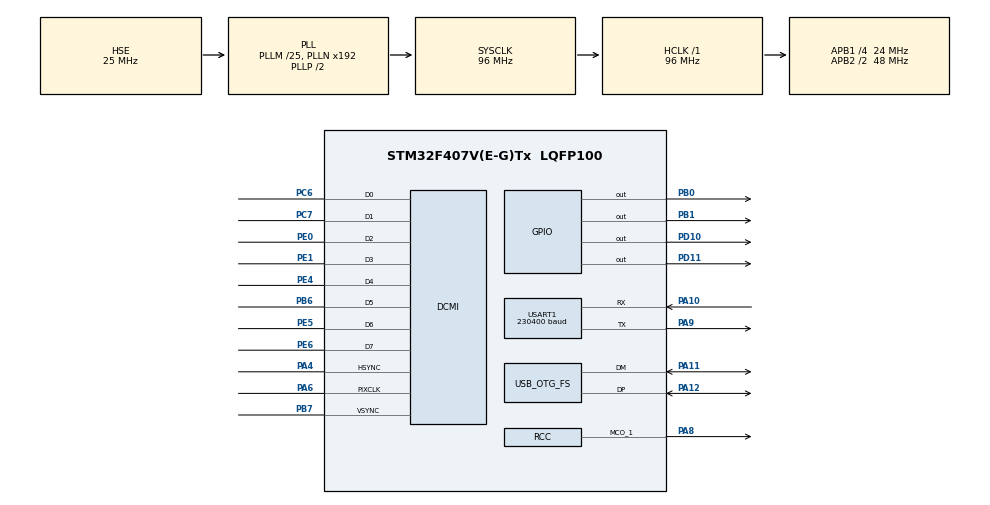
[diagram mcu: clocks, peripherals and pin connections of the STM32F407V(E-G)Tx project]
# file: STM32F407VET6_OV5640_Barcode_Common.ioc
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Mcu.Family=STM32F4
PA6.Mode=Slave_8_bits_External_Synchro
USB_DEVICE.CLASS_NAME_FS=CDC
PH0-OSC_IN.Signal=RCC_OSC_IN
RCC.CortexFreq_Value=96000000
DCMI.HSPolarity=DCMI_HSPOLARITY_LOW
Dma.USART1_TX.1.MemInc=DMA_MINC_ENABLE
PA10.GPIO_PuPd=GPIO_NOPULL
USART1.BaudRate=230400
PA11.Mode=Device_Only
USB_DEVICE.VirtualMode-CDC_FS=Cdc
Dma.DCMI.0.MemBurst=DMA_MBURST_SINGLE
RCC.SYSCLKSource=RCC_SYSCLKSOURCE_PLLCLK
ProjectManager.StackSize=0x2000
Dma.DCMI.0.FIFOMode=DMA_FIFOMODE_ENABLE
Dma.DCMI.0.MemDataAlignment=DMA_MDATAALIGN_WORD
Dma.USART1_TX.1.MemBurst=DMA_MBURST_SINGLE
Dma.DCMI.0.FIFOThreshold=DMA_FIFO_THRESHOLD_FULL
Dma.DCMI.0.MemInc=DMA_MINC_DISABLE
PA12.Signal=USB_OTG_FS_DP
PA4.Mode=Slave_8_bits_External_Synchro
Dma.DCMI.0.PeriphDataAlignment=DMA_PDATAALIGN_WORD
PB0.PinState=GPIO_PIN_SET
PB1.GPIO_PuPd=GPIO_PULLUP
RCC.HCLKFreq_Value=96000000
RCC.APB2TimFreq_Value=96000000
PB6.Signal=DCMI_D5
DCMI.VSPolarity=DCMI_VSPOLARITY_HIGH
PC7.Signal=DCMI_D1
PB6.Mode=Slave_8_bits_External_Synchro
PE5.Signal=DCMI_D6
PE1.Signal=DCMI_D3
RCC.AHBFreq_Value=96000000
PH0-OSC_IN.Mode=HSE-External-Oscillator
RCC.HSE_VALUE=25000000
PA4.GPIO_PuPd=GPIO_NOPULL
RCC.RCC_MCO1Source=RCC_MCO1SOURCE_PLLCLK
DCMI.PCKPolarity=DCMI_PCKPOLARITY_RISING
PA6.GPIO_PuPd=GPIO_NOPULL
PB1.GPIO_Speed=GPIO_SPEED_FREQ_VERY_HIGH
Dma.USART1_TX.1.FIFOThreshold=DMA_FIFO_THRESHOLD_FULL
RCC.RCC_MCODiv1=RCC_MCODIV_4
PB7.Signal=DCMI_VSYNC
PA8.Signal=RCC_MCO_1
Dma.DCMI.0.PeriphBurst=DMA_PBURST_SINGLE
PE4.Mode=Slave_8_bits_External_Synchro
PE4.Signal=DCMI_D4
Dma.USART1_TX.1.PeriphDataAlignment=DMA_PDATAALIGN_BYTE
PB1.PinState=GPIO_PIN_SET
PH1-OSC_OUT.Mode=HSE-External-Oscillator
Mcu.Package=LQFP100
PB1.Signal=GPIO_Output
PA6.Signal=DCMI_PIXCLK
NVIC.DMA2_Stream7_IRQn=true\:0\:0\:false\:false\:true\:false\:true
Dma.DCMI.0.Direction=DMA_PERIPH_TO_MEMORY
NVIC.OTG_FS_IRQn=true\:0\:0\:false\:false\:true\:true\:true
PA10.Signal=USART1_RX
USB_OTG_FS.VirtualMode=Device_Only
PA10.GPIO_Speed=GPIO_SPEED_FREQ_HIGH
RCC.APB2CLKDivider=RCC_HCLK_DIV2
Dma.Request1=USART1_TX
RCC.APB1TimFreq_Value=48000000
PB0.GPIO_ModeDefaultOutputPP=GPIO_MODE_OUTPUT_PP
Dma.USART1_TX.1.Priority=DMA_PRIORITY_MEDIUM
PA6.GPIO_Speed=GPIO_SPEED_FREQ_VERY_HIGH
NVIC.USART1_IRQn=true\:1\:0\:true\:true\:true\:1\:true\:true
Dma.Request0=DCMI
Dma.USART1_TX.1.Direction=DMA_MEMORY_TO_PERIPH
PB7.GPIO_PuPd=GPIO_NOPULL
Dma.USART1_TX.1.Instance=DMA2_Stream7
PA10.Mode=Asynchronous
USB_DEVICE.VirtualModeFS=Cdc_FS
PE1.Mode=Slave_8_bits_External_Synchro
PC6.Signal=DCMI_D0
NVIC.DMA2_Stream1_IRQn=true\:0\:0\:false\:false\:true\:false\:true
RCC.APB1CLKDivider=RCC_HCLK_DIV4
PB0.GPIO_Speed=GPIO_SPEED_FREQ_VERY_HIGH
PD10.Signal=GPIO_Output
Dma.USART1_TX.1.PeriphBurst=DMA_PBURST_SINGLE
PA9.Mode=Asynchronous
ProjectManager.TargetToolchain=STM32CubeIDE
PC6.Mode=Slave_8_bits_External_Synchro
VP_USB_DEVICE_VS_USB_DEVICE_CDC_FS.Mode=CDC_FS
PA9.Signal=USART1_TX
Dma.DCMI.0.Instance=DMA2_Stream1
Dma.DCMI.0.Mode=DMA_NORMAL
Dma.USART1_TX.1.FIFOMode=DMA_FIFOMODE_ENABLE
RCC.LSE_VALUE=32768
DCMI.JPEGMode=DCMI_JPEG_DISABLE
Dma.USART1_TX.1.MemDataAlignment=DMA_MDATAALIGN_BYTE
board=custom
RCC.VCOOutputFreq_Value=192000000
RCC.APB2Freq_Value=48000000
PE6.Mode=Slave_8_bits_External_Synchro
PE5.Mode=Slave_8_bits_External_Synchro
PH1-OSC_OUT.Signal=RCC_OSC_OUT
PE6.Signal=DCMI_D7
PE0.Signal=DCMI_D2
Mcu.Name=STM32F407V(E-G)Tx
RCC.48MHZClocksFreq_Value=48000000
PA4.Signal=DCMI_HSYNC
RCC.SYSCLKFreq_VALUE=96000000
PA12.Mode=Device_Only
PD11.Signal=GPIO_Output
Dma.USART1_TX.1.Mode=DMA_NORMAL
USART1.VirtualMode=VM_ASYNC
PB7.Mode=Slave_8_bits_External_Synchro
PA11.Signal=USB_OTG_FS_DM
ProjectManager.HeapSize=0x2000
Dma.USART1_TX.1.PeriphInc=DMA_PINC_DISABLE
PD10.PinState=GPIO_PIN_SET
RCC.HSI_VALUE=16000000
NVIC.PriorityGroup=NVIC_PRIORITYGROUP_4
RCC.PLLM=25
PA9.GPIO_Speed=GPIO_SPEED_FREQ_HIGH
Dma.DCMI.0.PeriphInc=DMA_PINC_DISABLE
PA8.Mode=Clock-out-1
NVIC.DCMI_IRQn=true\:0\:0\:false\:false\:true\:true\:true
PB1.GPIO_ModeDefaultOutputPP=GPIO_MODE_OUTPUT_PP
PC7.Mode=Slave_8_bits_External_Synchro
RCC.APB1Freq_Value=24000000
PB0.Signal=GPIO_Output
PE0.Mode=Slave_8_bits_External_Synchro
PB0.GPIO_PuPd=GPIO_PULLUP
Dma.DCMI.0.Priority=DMA_PRIORITY_HIGH

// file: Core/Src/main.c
/* USER CODE BEGIN Header */
/**
  ******************************************************************************
  * @file           : main.c
  * @brief          : Main program body
  ******************************************************************************
  * @attention
  *
  * <h2><center>&copy; Copyright (c) 2020 STMicroelectronics.
  * All rights reserved.</center></h2>
  *
  * This software component is licensed by ST under BSD 3-Clause license,
  * the "License"; You may not use this file except in compliance with the
  * License. You may obtain a copy of the License at:
  *                        opensource.org/licenses/BSD-3-Clause
  *
  ******************************************************************************
  */
/* USER CODE END Header */
#include "main.h"
#include "usb_device.h"

/* USER CODE BEGIN Includes */
#include "ov5640.h"

void DCMI_DMA_MemInc_En(void);
void DCMI_DMA_MemInc_Den(void);

/* USER CODE END Includes */

/* USER CODE BEGIN PTD */
uint8_t aRxBuffer=0;

uint8_t TxBuff[99] = {0};
uint8_t StatusFlag = 0;

uint8_t ov5640_reg1 = 0xff;
uint8_t ov5640_reg2 = 0xff;

HAL_StatusTypeDef dcmi_dma_status = HAL_OK;

uint32_t dcmi_data_buff[16000];

uint32_t DCMI_RN = 0;  //row number
uint32_t DCMI_CN = 0;  //column number
uint32_t DCMI_RS = 0;  //row start
uint32_t DCMI_CS = 0;  //column start

uint8_t scmd = 0;
uint8_t tx_busy = 0;
/* USER CODE END PTD */

DCMI_HandleTypeDef hdcmi;
DMA_HandleTypeDef hdma_dcmi;

UART_HandleTypeDef huart1;
DMA_HandleTypeDef hdma_usart1_tx;

void SystemClock_Config(void);
static void MX_GPIO_Init(void);
static void MX_DMA_Init(void);
static void MX_USART1_UART_Init(void);
static void MX_DCMI_Init(void);
static void MX_NVIC_Init(void);

int main(void)
{

  /* MCU Configuration--------------------------------------------------------*/

  /* Reset of all peripherals, Initializes the Flash interface and the Systick. */
  HAL_Init();

  /* Configure the system clock */
  SystemClock_Config();

  /* Initialize all configured peripherals */
  MX_GPIO_Init();
  MX_DMA_Init();
  MX_USART1_UART_Init();
  MX_DCMI_Init();
  MX_USB_DEVICE_Init();

  /* Initialize interrupts */
  MX_NVIC_Init();
  /* USER CODE BEGIN 2 */

  if (HAL_UART_Receive_IT(&huart1, (uint8_t *)&aRxBuffer, 1)!=HAL_OK)
   {
 	  MX_USART1_UART_Init();
 	  HAL_UART_Receive_IT(&huart1, (uint8_t *)&aRxBuffer, 1);
   }

     HAL_Delay(500); //Await OV5640 running stable
     SCCB_Rst();
     HAL_Delay(100);

 	 ov5640_reg1 = SCCB_RD_Reg(OV5640_CHIPIDH);
 	 ov5640_reg2 = SCCB_RD_Reg(OV5640_CHIPIDL);
     if((ov5640_reg1==0xff)||(ov5640_reg2==0xff)) while(1);;

 	   OV5640_Init(); HAL_Delay(1);
 	   OV5640_RGB565_Mode(); HAL_Delay(1);
 	   OV5640_Focus_Init(); HAL_Delay(1);
 	   ov5640_speed_ctrl(); HAL_Delay(1);
 	   OV5640_OutSize_Set(16,4,640,482); HAL_Delay(1);

  /* USER CODE END 2 */

  /* Infinite loop */
  while (1)
  {

    /* USER CODE BEGIN 3 */
	 	HAL_Delay(1);

	    if (scmd==1)
	    {
	    	scmd = 0;

	    	  OV5640_Focus_Single();

	      	  DCMI_DMA_MemInc_En();
	      	  HAL_DCMI_DisableCrop (&hdcmi);
	       	  TxBuff[0]=0x55;
	          TxBuff[1]=0xaa;
	          TxBuff[2]=0x03; //OV5640 Label
	          CDC_Transmit_FS(TxBuff, 3);
	          HAL_Delay(100);

       	      dcmi_dma_status = HAL_DCMI_Init(&hdcmi);
	    	  for (uint8_t i=0; i<10;i++)
	    	  {
	 		     HAL_DCMI_DisableCrop (&hdcmi);

	 	    	 DCMI_RN = 48;
	 	    	 DCMI_CN = 1280;

	 	    	 DCMI_RS = 48*i;
	 	    	 DCMI_CS = 0;

	 	    	 HAL_DCMI_ConfigCrop (&hdcmi, DCMI_CS, DCMI_RS, DCMI_CN, DCMI_RN);
	 	    	 HAL_Delay(1);
	 	    	 HAL_DCMI_EnableCrop (&hdcmi);
	 	    	 HAL_Delay(1);

	 	    	 dcmi_dma_status = HAL_DCMI_Start_DMA(&hdcmi, DCMI_MODE_SNAPSHOT, dcmi_data_buff, DCMI_CN*DCMI_RN/4);
	 	    	 while(HAL_DMA_GetState(&hdcmi)==HAL_DMA_STATE_BUSY) ;
	 	    	 HAL_DCMI_Stop(&hdcmi);

	 	    	 tx_busy = 1;
 		    	 CDC_Transmit_FS((uint8_t *)dcmi_data_buff, 61440);
 		    	 while(tx_busy!=0) ;
	    	  }
	    }

	    if (scmd==2)
	    {
	    	scmd = 0;

	    	 OV5640_Focus_Single();

	      	  DCMI_DMA_MemInc_En();
	      	  HAL_DCMI_DisableCrop (&hdcmi);
	       	  TxBuff[0]=0x55;
	          TxBuff[1]=0xaa;
	          TxBuff[2]=0x03; //OV5640 Label
	      	  HAL_UART_Transmit(&huart1, TxBuff, 3, 0xFFFFFF);
	          HAL_Delay(100);

       	      dcmi_dma_status = HAL_DCMI_Init(&hdcmi);
	    	  for (uint8_t i=0; i<10;i++)
	    	  {
	 		     HAL_DCMI_DisableCrop (&hdcmi);

	 	    	 DCMI_RN = 48;
	 	    	 DCMI_CN = 1280;

	 	    	 DCMI_RS = 48*i;
	 	    	 DCMI_CS = 0;

	 	    	 HAL_DCMI_ConfigCrop (&hdcmi, DCMI_CS, DCMI_RS, DCMI_CN, DCMI_RN);
	 	    	 HAL_Delay(1);
	 	    	 HAL_DCMI_EnableCrop (&hdcmi);
	 	    	 HAL_Delay(1);

	 	    	 dcmi_dma_status = HAL_DCMI_Start_DMA(&hdcmi, DCMI_MODE_SNAPSHOT, dcmi_data_buff, DCMI_CN*DCMI_RN/4);
	 	    	 while(HAL_DMA_GetState(&hdcmi)==HAL_DMA_STATE_BUSY) ;
	 	    	 HAL_DCMI_Stop(&hdcmi);

	 	    	  tx_busy = 1;
	 	    	  HAL_UART_Transmit_DMA(&huart1, (uint8_t *)dcmi_data_buff, 61440);
   		          while(tx_busy!=0) ;
	    	  }
	    }

}
  /* USER CODE END 3 */
}

void SystemClock_Config(void)
{
  RCC_OscInitTypeDef RCC_OscInitStruct = {0};
  RCC_ClkInitTypeDef RCC_ClkInitStruct = {0};

  /** Configure the main internal regulator output voltage
  */
  __HAL_RCC_PWR_CLK_ENABLE();
  __HAL_PWR_VOLTAGESCALING_CONFIG(PWR_REGULATOR_VOLTAGE_SCALE1);
  /** Initializes the RCC Oscillators according to the specified parameters
  * in the RCC_OscInitTypeDef structure.
  */
  RCC_OscInitStruct.OscillatorType = RCC_OSCILLATORTYPE_HSE;
  RCC_OscInitStruct.HSEState = RCC_HSE_ON;
  RCC_OscInitStruct.PLL.PLLState = RCC_PLL_ON;
  RCC_OscInitStruct.PLL.PLLSource = RCC_PLLSOURCE_HSE;
  RCC_OscInitStruct.PLL.PLLM = 25;
  RCC_OscInitStruct.PLL.PLLN = 192;
  RCC_OscInitStruct.PLL.PLLP = RCC_PLLP_DIV2;
  RCC_OscInitStruct.PLL.PLLQ = 4;
  if (HAL_RCC_OscConfig(&RCC_OscInitStruct) != HAL_OK)
  {
    Error_Handler();
  }
  /** Initializes the CPU, AHB and APB buses clocks
  */
  RCC_ClkInitStruct.ClockType = RCC_CLOCKTYPE_HCLK|RCC_CLOCKTYPE_SYSCLK
                              |RCC_CLOCKTYPE_PCLK1|RCC_CLOCKTYPE_PCLK2;
  RCC_ClkInitStruct.SYSCLKSource = RCC_SYSCLKSOURCE_PLLCLK;
  RCC_ClkInitStruct.AHBCLKDivider = RCC_SYSCLK_DIV1;
  RCC_ClkInitStruct.APB1CLKDivider = RCC_HCLK_DIV4;
  RCC_ClkInitStruct.APB2CLKDivider = RCC_HCLK_DIV2;

  if (HAL_RCC_ClockConfig(&RCC_ClkInitStruct, FLASH_LATENCY_3) != HAL_OK)
  {
    Error_Handler();
  }
  HAL_RCC_MCOConfig(RCC_MCO1, RCC_MCO1SOURCE_PLLCLK, RCC_MCODIV_4);
}

/**
  * @brief NVIC Configuration.
  * @retval None
  */
static void MX_NVIC_Init(void)
{
  /* USART1_IRQn interrupt configuration */
  HAL_NVIC_SetPriority(USART1_IRQn, 1, 0);
  HAL_NVIC_EnableIRQ(USART1_IRQn);
}

static void MX_DCMI_Init(void)
{

  hdcmi.Instance = DCMI;
  hdcmi.Init.SynchroMode = DCMI_SYNCHRO_HARDWARE;
  hdcmi.Init.PCKPolarity = DCMI_PCKPOLARITY_RISING;
  hdcmi.Init.VSPolarity = DCMI_VSPOLARITY_HIGH;
  hdcmi.Init.HSPolarity = DCMI_HSPOLARITY_LOW;
  hdcmi.Init.CaptureRate = DCMI_CR_ALL_FRAME;
  hdcmi.Init.ExtendedDataMode = DCMI_EXTEND_DATA_8B;
  hdcmi.Init.JPEGMode = DCMI_JPEG_DISABLE;
  if (HAL_DCMI_Init(&hdcmi) != HAL_OK)
  {
    Error_Handler();
  }

}

static void MX_USART1_UART_Init(void)
{

  huart1.Instance = USART1;
  huart1.Init.BaudRate = 230400;
  huart1.Init.WordLength = UART_WORDLENGTH_8B;
  huart1.Init.StopBits = UART_STOPBITS_1;
  huart1.Init.Parity = UART_PARITY_NONE;
  huart1.Init.Mode = UART_MODE_TX_RX;
  huart1.Init.HwFlowCtl = UART_HWCONTROL_NONE;
  huart1.Init.OverSampling = UART_OVERSAMPLING_16;
  if (HAL_UART_Init(&huart1) != HAL_OK)
  {
    Error_Handler();
  }

}

static void MX_DMA_Init(void)
{

  /* DMA controller clock enable */
  __HAL_RCC_DMA2_CLK_ENABLE();

  /* DMA interrupt init */
  /* DMA2_Stream1_IRQn interrupt configuration */
  HAL_NVIC_SetPriority(DMA2_Stream1_IRQn, 0, 0);
  HAL_NVIC_EnableIRQ(DMA2_Stream1_IRQn);
  /* DMA2_Stream7_IRQn interrupt configuration */
  HAL_NVIC_SetPriority(DMA2_Stream7_IRQn, 0, 0);
  HAL_NVIC_EnableIRQ(DMA2_Stream7_IRQn);

}

static void MX_GPIO_Init(void)
{
  GPIO_InitTypeDef GPIO_InitStruct = {0};

  /* GPIO Ports Clock Enable */
  __HAL_RCC_GPIOE_CLK_ENABLE();
  __HAL_RCC_GPIOH_CLK_ENABLE();
  __HAL_RCC_GPIOA_CLK_ENABLE();
  __HAL_RCC_GPIOB_CLK_ENABLE();
  __HAL_RCC_GPIOD_CLK_ENABLE();
  __HAL_RCC_GPIOC_CLK_ENABLE();

  /*Configure GPIO pin Output Level */
  HAL_GPIO_WritePin(GPIOB, GPIO_PIN_8|GPIO_PIN_9, GPIO_PIN_SET);

  /*Configure GPIO pin Output Level */
  HAL_GPIO_WritePin(GPIOD, GPIO_PIN_10, GPIO_PIN_SET);

  /*Configure GPIO pin Output Level */
  HAL_GPIO_WritePin(GPIOD, GPIO_PIN_11, GPIO_PIN_RESET);

  /*Configure GPIO pins : PB0 PB1 */
  GPIO_InitStruct.Pin = GPIO_PIN_8|GPIO_PIN_9;
  GPIO_InitStruct.Mode = GPIO_MODE_OUTPUT_PP;
  GPIO_InitStruct.Pull = GPIO_PULLUP;
  GPIO_InitStruct.Speed = GPIO_SPEED_FREQ_VERY_HIGH;
  HAL_GPIO_Init(GPIOB, &GPIO_InitStruct);

  /*Configure GPIO pins : PD10 PD11 */
  GPIO_InitStruct.Pin = GPIO_PIN_10|GPIO_PIN_11;
  GPIO_InitStruct.Mode = GPIO_MODE_OUTPUT_PP;
  GPIO_InitStruct.Pull = GPIO_NOPULL;
  GPIO_InitStruct.Speed = GPIO_SPEED_FREQ_LOW;
  HAL_GPIO_Init(GPIOD, &GPIO_InitStruct);

  /*Configure GPIO pin : PA8 */
  GPIO_InitStruct.Pin = GPIO_PIN_8;
  GPIO_InitStruct.Mode = GPIO_MODE_AF_PP;
  GPIO_InitStruct.Pull = GPIO_NOPULL;
  GPIO_InitStruct.Speed = GPIO_SPEED_FREQ_LOW;
  GPIO_InitStruct.Alternate = GPIO_AF0_MCO;
  HAL_GPIO_Init(GPIOA, &GPIO_InitStruct);

}

/* USER CODE BEGIN 4 */
void HAL_UART_RxCpltCallback(UART_HandleTypeDef *huart)
{
	if (huart ==  &huart1)
	{

		if (aRxBuffer==0x01)
		{
			scmd = 0x02;
			aRxBuffer=0x00;

			HAL_UART_Receive_IT(&huart1, (uint8_t *)&aRxBuffer, 1);
		}
		else
		{

		HAL_UART_Receive_IT(&huart1, (uint8_t *)&aRxBuffer, 1);

		}

	}
      return;

}

void HAL_UART_TxCpltCallback(UART_HandleTypeDef *huart)
{

	if (huart ==  &huart1)
	{
		tx_busy = 0;
	}

}

void DCMI_DMA_MemInc_En(void)
{
    HAL_DMA_DeInit(&hdma_dcmi);

    hdma_dcmi.Init.MemInc = DMA_MINC_ENABLE;
    if (HAL_DMA_Init(&hdma_dcmi) != HAL_OK)
    {
      Error_Handler();
    }
}

void DCMI_DMA_MemInc_Den(void)
{
    HAL_DMA_DeInit(&hdma_dcmi);
    hdma_dcmi.Init.MemInc = DMA_MINC_DISABLE;
    if (HAL_DMA_Init(&hdma_dcmi) != HAL_OK)
    {
      Error_Handler();
    }
}

/* USER CODE END 4 */

void Error_Handler(void)
{
}

/************************ (C) COPYRIGHT STMicroelectronics *****END OF FILE****/
